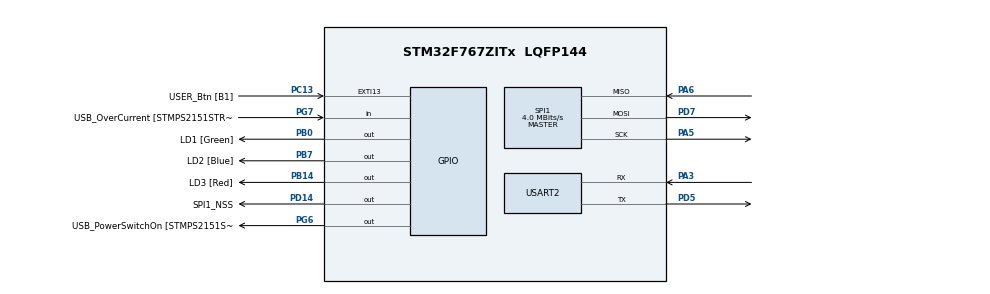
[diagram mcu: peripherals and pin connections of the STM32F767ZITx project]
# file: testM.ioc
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Dma.Request0=SPI1_RX
Dma.Request1=SPI1_TX
Dma.Request2=USART2_RX
Dma.Request3=USART2_TX
Dma.SPI1_RX.0.Direction=DMA_PERIPH_TO_MEMORY
Dma.SPI1_RX.0.FIFOMode=DMA_FIFOMODE_DISABLE
Dma.SPI1_RX.0.Instance=DMA2_Stream0
Dma.SPI1_RX.0.MemDataAlignment=DMA_MDATAALIGN_BYTE
Dma.SPI1_RX.0.MemInc=DMA_MINC_ENABLE
Dma.SPI1_RX.0.Mode=DMA_NORMAL
Dma.SPI1_RX.0.PeriphDataAlignment=DMA_PDATAALIGN_BYTE
Dma.SPI1_RX.0.PeriphInc=DMA_PINC_DISABLE
Dma.SPI1_RX.0.Priority=DMA_PRIORITY_LOW
Dma.SPI1_TX.1.Direction=DMA_MEMORY_TO_PERIPH
Dma.SPI1_TX.1.FIFOMode=DMA_FIFOMODE_DISABLE
Dma.SPI1_TX.1.Instance=DMA2_Stream3
Dma.SPI1_TX.1.MemDataAlignment=DMA_MDATAALIGN_BYTE
Dma.SPI1_TX.1.MemInc=DMA_MINC_ENABLE
Dma.SPI1_TX.1.Mode=DMA_NORMAL
Dma.SPI1_TX.1.PeriphDataAlignment=DMA_PDATAALIGN_BYTE
Dma.SPI1_TX.1.PeriphInc=DMA_PINC_DISABLE
Dma.SPI1_TX.1.Priority=DMA_PRIORITY_LOW
Dma.USART2_RX.2.Direction=DMA_PERIPH_TO_MEMORY
Dma.USART2_RX.2.FIFOMode=DMA_FIFOMODE_DISABLE
Dma.USART2_RX.2.Instance=DMA1_Stream5
Dma.USART2_RX.2.MemDataAlignment=DMA_MDATAALIGN_BYTE
Dma.USART2_RX.2.MemInc=DMA_MINC_ENABLE
Dma.USART2_RX.2.Mode=DMA_NORMAL
Dma.USART2_RX.2.PeriphDataAlignment=DMA_PDATAALIGN_BYTE
Dma.USART2_RX.2.PeriphInc=DMA_PINC_DISABLE
Dma.USART2_RX.2.Priority=DMA_PRIORITY_MEDIUM
Dma.USART2_TX.3.Direction=DMA_MEMORY_TO_PERIPH
Dma.USART2_TX.3.FIFOMode=DMA_FIFOMODE_DISABLE
Dma.USART2_TX.3.Instance=DMA1_Stream6
Dma.USART2_TX.3.MemDataAlignment=DMA_MDATAALIGN_BYTE
Dma.USART2_TX.3.MemInc=DMA_MINC_ENABLE
Dma.USART2_TX.3.Mode=DMA_NORMAL
Dma.USART2_TX.3.PeriphDataAlignment=DMA_PDATAALIGN_BYTE
Dma.USART2_TX.3.PeriphInc=DMA_PINC_DISABLE
Dma.USART2_TX.3.Priority=DMA_PRIORITY_MEDIUM
Mcu.Family=STM32F7
Mcu.Name=STM32F767ZITx
Mcu.Package=LQFP144
NVIC.DMA1_Stream5_IRQn=true\:0\:0\:false\:false\:true\:false\:true\:true
NVIC.DMA1_Stream6_IRQn=true\:0\:0\:false\:false\:true\:false\:true\:true
NVIC.DMA2_Stream0_IRQn=true\:0\:0\:false\:false\:true\:false\:true\:true
NVIC.DMA2_Stream3_IRQn=true\:0\:0\:false\:false\:true\:false\:true\:true
NVIC.PriorityGroup=NVIC_PRIORITYGROUP_4
NVIC.SPI1_IRQn=true\:0\:0\:false\:false\:true\:true\:true\:true
NVIC.USART2_IRQn=true\:0\:0\:false\:false\:true\:true\:true\:true
PA1.GPIO_Label=RMII_REF_CLK [LAN8742A-CZ-TR_REFCLK0]
PA1.Signal=ETH_REF_CLK
PA10.GPIO_Label=USB_ID
PA10.Signal=USB_OTG_FS_ID
PA11.GPIO_Label=USB_DM
PA11.Signal=USB_OTG_FS_DM
PA12.GPIO_Label=USB_DP
PA12.Signal=USB_OTG_FS_DP
PA13.GPIO_Label=TMS
PA13.Signal=SYS_JTMS-SWDIO
PA14.GPIO_Label=TCK
PA14.Signal=SYS_JTCK-SWCLK
PA2.GPIO_Label=RMII_MDIO [LAN8742A-CZ-TR_MDIO]
PA2.Signal=ETH_MDIO
PA3.Mode=Asynchronous
PA3.Signal=USART2_RX
PA5.Mode=Full_Duplex_Master
PA5.Signal=SPI1_SCK
PA6.Mode=Full_Duplex_Master
PA6.Signal=SPI1_MISO
PA7.GPIO_Label=RMII_CRS_DV [LAN8742A-CZ-TR_CRS_DV]
PA7.Signal=ETH_CRS_DV
PA8.GPIO_Label=USB_SOF [TP1]
PA8.Signal=USB_OTG_FS_SOF
PA9.GPIO_Label=USB_VBUS
PA9.Signal=USB_OTG_FS_VBUS
PB0.GPIO_Label=LD1 [Green]
PB0.Signal=GPIO_Output
PB13.GPIO_Label=RMII_TXD1 [LAN8742A-CZ-TR_TXD1]
PB13.Signal=ETH_TXD1
PB14.GPIO_Label=LD3 [Red]
PB14.Signal=GPIO_Output
PB3.GPIO_Label=SW0
PB3.Signal=SYS_JTDO-SWO
PB7.GPIO_Label=LD2 [Blue]
PB7.Signal=GPIO_Output
PC1.GPIO_Label=RMII_MDC [LAN8742A-CZ-TR_MDC]
PC1.Signal=ETH_MDC
PC13.GPIO_Label=USER_Btn [B1]
PC13.Signal=GPXTI13
PC14/OSC32_IN.Signal=RCC_OSC32_IN
PC15/OSC32_OUT.Signal=RCC_OSC32_OUT
PC4.GPIO_Label=RMII_RXD0 [LAN8742A-CZ-TR_RXD0]
PC4.Signal=ETH_RXD0
PC5.GPIO_Label=RMII_RXD1 [LAN8742A-CZ-TR_RXD1]
PC5.Signal=ETH_RXD1
PD14.GPIO_Label=SPI1_NSS
PD14.GPIO_PuPd=GPIO_NOPULL
PD14.Signal=GPIO_Output
PD5.Mode=Asynchronous
PD5.Signal=USART2_TX
PD7.Mode=Full_Duplex_Master
PD7.Signal=SPI1_MOSI
PD8.GPIO_Label=STLK_RX [STM32F103CBT6_PA3]
PD8.Signal=USART3_TX
PD9.GPIO_Label=STLK_TX [STM32F103CBT6_PA2]
PD9.Signal=USART3_RX
PG11.GPIO_Label=RMII_TX_EN [LAN8742A-CZ-TR_TXEN]
PG11.Signal=ETH_TX_EN
PG13.GPIO_Label=RMII_TXD0 [LAN8742A-CZ-TR_TXD0]
PG13.Signal=ETH_TXD0
PG6.GPIO_Label=USB_PowerSwitchOn [STMPS2151STR_EN]
PG6.Signal=GPIO_Output
PG7.GPIO_Label=USB_OverCurrent [STMPS2151STR_FAULT]
PG7.Signal=GPIO_Input
PH0/OSC_IN.GPIO_Label=MCO [STM32F103CBT6_PA8]
PH0/OSC_IN.Signal=RCC_OSC_IN
PH1/OSC_OUT.Signal=RCC_OSC_OUT
ProjectManager.HeapSize=0x200
ProjectManager.StackSize=0x400
ProjectManager.TargetToolchain=STM32CubeIDE
RCC.48MHZClocksFreq_Value=24000000
RCC.AHBFreq_Value=16000000
RCC.APB1CLKDivider=RCC_HCLK_DIV2
RCC.APB1Freq_Value=8000000
RCC.APB1TimFreq_Value=16000000
RCC.APB2Freq_Value=16000000
RCC.APB2TimFreq_Value=16000000
RCC.CortexFreq_Value=16000000
RCC.HCLKFreq_Value=16000000
RCC.HSE_VALUE=16000000
RCC.HSI_VALUE=16000000
RCC.LSE_VALUE=32768
RCC.PLLMUL=RCC_PLL_MUL9
RCC.PRESCALERUSB=RCC_USBCLKSOURCE_PLL_DIV1_5
RCC.SYSCLKFreq_VALUE=16000000
RCC.SYSCLKSourceVirtual=RCC_SYSCLKSOURCE_PLLCLK
RCC.USBFreq_Value=96000000
RCC.VCOOutputFreq_Value=192000000
SPI1.BaudRatePrescaler=SPI_BAUDRATEPRESCALER_4
SPI1.CalculateBaudRate=4.0 MBits/s
SPI1.DataSize=SPI_DATASIZE_8BIT
SPI1.Direction=SPI_DIRECTION_2LINES
SPI1.Mode=SPI_MODE_MASTER
SPI1.VirtualType=VM_MASTER
USART2.VirtualMode-Asynchronous=VM_ASYNC
VP_CRC_VS_CRC.Mode=CRC_Activate
board=NUCLEO-F767ZI

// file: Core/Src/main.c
/* USER CODE BEGIN Header */
/**
  ******************************************************************************
  * @file           : main.c
  * @brief          : Main program body
  ******************************************************************************
  * @attention
  *
  * Copyright (c) 2026 STMicroelectronics.
  * All rights reserved.
  *
  * This software is licensed under terms that can be found in the LICENSE file
  * in the root directory of this software component.
  * If no LICENSE file comes with this software, it is provided AS-IS.
  *
  ******************************************************************************
  */
/* USER CODE END Header */
#include "main.h"

/* USER CODE BEGIN Includes */
#include <stdio.h>
#include <string.h>
/* USER CODE END Includes */

/* USER CODE BEGIN PTD */
#define DATA_SIZE 512

// Structure de la trame de 520 octets
typedef struct __attribute__((packed)) {
    uint8_t  cmd;           // 0x01: Write, 0x02: Erase,
    uint32_t addr;          // Adresse Flash de destination
    uint16_t len;           // Toujours 512
    uint8_t  data[DATA_SIZE]; // Les données à flasher
    uint8_t  crc;           // XOR de vérification
} SpiFrame_t;
/* USER CODE END PTD */

CRC_HandleTypeDef hcrc;

SPI_HandleTypeDef hspi1;
DMA_HandleTypeDef hdma_spi1_rx;
DMA_HandleTypeDef hdma_spi1_tx;

UART_HandleTypeDef huart2;
DMA_HandleTypeDef hdma_usart2_rx;
DMA_HandleTypeDef hdma_usart2_tx;

/* USER CODE BEGIN PV */
uint8_t msg[] = "Communication via ST-LINK V3 CN3 : OK\r\n";
__attribute__((aligned(32))) SpiFrame_t frame_A;
__attribute__((aligned(32)))   SpiFrame_t frame_B;

SpiFrame_t *uart_rx_ptr = &frame_A;
SpiFrame_t *spi_tx_ptr  = &frame_B;

volatile uint8_t uart_rx_ready = 0;
__attribute__((aligned(32))) volatile uint8_t spi_tx_complete = 1;
volatile uint32_t dbg_bridge_count = 0;
/* USER CODE END PV */

void SystemClock_Config(void);
static void MX_GPIO_Init(void);
static void MX_DMA_Init(void);
static void MX_SPI1_Init(void);
static void MX_USART2_UART_Init(void);
static void MX_CRC_Init(void);
/* USER CODE BEGIN PFP */
void Send_SPI_Bridge_Frame(SpiFrame_t *frame_ptr);
void Enable_NonCacheable_Regions(void); // Add this line
/* USER CODE END PFP */

int main(void)
{

  /* MCU Configuration--------------------------------------------------------*/

  /* Reset of all peripherals, Initializes the Flash interface and the Systick. */
  HAL_Init();

  /* USER CODE BEGIN Init */
  Enable_NonCacheable_Regions();
  /* USER CODE END Init */

  /* Configure the system clock */
  SystemClock_Config();

  /* Initialize all configured peripherals */
  MX_GPIO_Init();
  MX_DMA_Init();
  MX_SPI1_Init();
  MX_USART2_UART_Init();
  MX_CRC_Init();
  /* USER CODE BEGIN 2 */
  HAL_GPIO_WritePin(GPIOD, SPI1_NSS_Pin, GPIO_PIN_SET);
  HAL_UART_Receive_DMA(&huart2, (uint8_t*)uart_rx_ptr, sizeof(SpiFrame_t));
  /* USER CODE END 2 */

  /* Infinite loop */
  /* USER CODE BEGIN WHILE */
  while (1)
  {
		if (uart_rx_ready)
	    	    {
	    	        uart_rx_ready = 0;
	    	        Send_SPI_Bridge_Frame(spi_tx_ptr);
	    	        dbg_bridge_count++;
	    	        HAL_GPIO_TogglePin(GPIOB, LD1_Pin);
	    	    }
    /* USER CODE END WHILE */

  }
}

void SystemClock_Config(void)
{
  RCC_OscInitTypeDef RCC_OscInitStruct = {0};
  RCC_ClkInitTypeDef RCC_ClkInitStruct = {0};

  __HAL_RCC_PWR_CLK_ENABLE();
  __HAL_PWR_VOLTAGESCALING_CONFIG(PWR_REGULATOR_VOLTAGE_SCALE1);

  // Configuration PLL pour 216MHz à partir du HSI (16MHz)
  RCC_OscInitStruct.OscillatorType = RCC_OSCILLATORTYPE_HSI;
  RCC_OscInitStruct.HSIState = RCC_HSI_ON;
  RCC_OscInitStruct.HSICalibrationValue = RCC_HSICALIBRATION_DEFAULT;
  RCC_OscInitStruct.PLL.PLLState = RCC_PLL_ON;
  RCC_OscInitStruct.PLL.PLLSource = RCC_PLLSOURCE_HSI;
  RCC_OscInitStruct.PLL.PLLM = 8;
  RCC_OscInitStruct.PLL.PLLN = 216;
  RCC_OscInitStruct.PLL.PLLP = RCC_PLLP_DIV2;
  RCC_OscInitStruct.PLL.PLLQ = 2;
  if (HAL_RCC_OscConfig(&RCC_OscInitStruct) != HAL_OK) { Error_Handler(); }

  // Activation de l'OverDrive pour atteindre 216MHz
  if (HAL_PWREx_EnableOverDrive() != HAL_OK) { Error_Handler(); }

  RCC_ClkInitStruct.ClockType = RCC_CLOCKTYPE_HCLK|RCC_CLOCKTYPE_SYSCLK
                              |RCC_CLOCKTYPE_PCLK1|RCC_CLOCKTYPE_PCLK2;
  RCC_ClkInitStruct.SYSCLKSource = RCC_SYSCLKSOURCE_PLLCLK;
  RCC_ClkInitStruct.AHBCLKDivider = RCC_SYSCLK_DIV1;
  RCC_ClkInitStruct.APB1CLKDivider = RCC_HCLK_DIV4;
  RCC_ClkInitStruct.APB2CLKDivider = RCC_HCLK_DIV2;

  if (HAL_RCC_ClockConfig(&RCC_ClkInitStruct, FLASH_LATENCY_7) != HAL_OK) { Error_Handler(); }
}

static void MX_CRC_Init(void)
{

  hcrc.Instance = CRC;
  hcrc.Init.DefaultPolynomialUse = DEFAULT_POLYNOMIAL_ENABLE;
  hcrc.Init.DefaultInitValueUse = DEFAULT_INIT_VALUE_ENABLE;
  hcrc.Init.InputDataInversionMode = CRC_INPUTDATA_INVERSION_NONE;
  hcrc.Init.OutputDataInversionMode = CRC_OUTPUTDATA_INVERSION_DISABLE;
  hcrc.InputDataFormat = CRC_INPUTDATA_FORMAT_BYTES;
  if (HAL_CRC_Init(&hcrc) != HAL_OK)
  {
    Error_Handler();
  }

}

static void MX_SPI1_Init(void)
{

  /* SPI1 parameter configuration*/
  hspi1.Instance = SPI1;
  hspi1.Init.Mode = SPI_MODE_MASTER;
  hspi1.Init.Direction = SPI_DIRECTION_2LINES;
  hspi1.Init.DataSize = SPI_DATASIZE_8BIT;
  hspi1.Init.CLKPolarity = SPI_POLARITY_LOW;
  hspi1.Init.CLKPhase = SPI_PHASE_1EDGE;
  hspi1.Init.NSS = SPI_NSS_SOFT;
  hspi1.Init.BaudRatePrescaler = SPI_BAUDRATEPRESCALER_16;
  hspi1.Init.FirstBit = SPI_FIRSTBIT_MSB;
  hspi1.Init.TIMode = SPI_TIMODE_DISABLE;
  hspi1.Init.CRCCalculation = SPI_CRCCALCULATION_DISABLE;
  hspi1.Init.CRCPolynomial = 7;
  hspi1.Init.CRCLength = SPI_CRC_LENGTH_DATASIZE;
  hspi1.Init.NSSPMode = SPI_NSS_PULSE_DISABLE;
  if (HAL_SPI_Init(&hspi1) != HAL_OK)
  {
    Error_Handler();
  }

}

static void MX_USART2_UART_Init(void)
{

  huart2.Instance = USART2;
  huart2.Init.BaudRate = 115200;
  huart2.Init.WordLength = UART_WORDLENGTH_8B;
  huart2.Init.StopBits = UART_STOPBITS_1;
  huart2.Init.Parity = UART_PARITY_NONE;
  huart2.Init.Mode = UART_MODE_TX_RX;
  huart2.Init.HwFlowCtl = UART_HWCONTROL_NONE;
  huart2.Init.OverSampling = UART_OVERSAMPLING_16;
  huart2.Init.OneBitSampling = UART_ONE_BIT_SAMPLE_DISABLE;
  huart2.AdvancedInit.AdvFeatureInit = UART_ADVFEATURE_NO_INIT;
  if (HAL_UART_Init(&huart2) != HAL_OK)
  {
    Error_Handler();
  }

}

static void MX_DMA_Init(void)
{

  /* DMA controller clock enable */
  __HAL_RCC_DMA2_CLK_ENABLE();
  __HAL_RCC_DMA1_CLK_ENABLE();

  /* DMA interrupt init */
  /* DMA1_Stream5_IRQn interrupt configuration */
  HAL_NVIC_SetPriority(DMA1_Stream5_IRQn, 0, 0);
  HAL_NVIC_EnableIRQ(DMA1_Stream5_IRQn);
  /* DMA1_Stream6_IRQn interrupt configuration */
  HAL_NVIC_SetPriority(DMA1_Stream6_IRQn, 0, 0);
  HAL_NVIC_EnableIRQ(DMA1_Stream6_IRQn);
  /* DMA2_Stream0_IRQn interrupt configuration */
  HAL_NVIC_SetPriority(DMA2_Stream0_IRQn, 0, 0);
  HAL_NVIC_EnableIRQ(DMA2_Stream0_IRQn);
  /* DMA2_Stream3_IRQn interrupt configuration */
  HAL_NVIC_SetPriority(DMA2_Stream3_IRQn, 0, 0);
  HAL_NVIC_EnableIRQ(DMA2_Stream3_IRQn);

}

static void MX_GPIO_Init(void)
{
  GPIO_InitTypeDef GPIO_InitStruct = {0};

  /* GPIO Ports Clock Enable */
  __HAL_RCC_GPIOC_CLK_ENABLE();
  __HAL_RCC_GPIOH_CLK_ENABLE();
  __HAL_RCC_GPIOA_CLK_ENABLE();
  __HAL_RCC_GPIOB_CLK_ENABLE();
  __HAL_RCC_GPIOD_CLK_ENABLE();
  __HAL_RCC_GPIOG_CLK_ENABLE();

  /*Configure GPIO pin Output Level */
  HAL_GPIO_WritePin(GPIOB, LD1_Pin|LD3_Pin|LD2_Pin, GPIO_PIN_RESET);

  /*Configure GPIO pin Output Level */
  HAL_GPIO_WritePin(SPI1_NSS_GPIO_Port, SPI1_NSS_Pin, GPIO_PIN_RESET);

  /*Configure GPIO pin Output Level */
  HAL_GPIO_WritePin(USB_PowerSwitchOn_GPIO_Port, USB_PowerSwitchOn_Pin, GPIO_PIN_RESET);

  /*Configure GPIO pin : USER_Btn_Pin */
  GPIO_InitStruct.Pin = USER_Btn_Pin;
  GPIO_InitStruct.Mode = GPIO_MODE_IT_RISING;
  GPIO_InitStruct.Pull = GPIO_NOPULL;
  HAL_GPIO_Init(USER_Btn_GPIO_Port, &GPIO_InitStruct);

  /*Configure GPIO pins : RMII_MDC_Pin RMII_RXD0_Pin RMII_RXD1_Pin */
  GPIO_InitStruct.Pin = RMII_MDC_Pin|RMII_RXD0_Pin|RMII_RXD1_Pin;
  GPIO_InitStruct.Mode = GPIO_MODE_AF_PP;
  GPIO_InitStruct.Pull = GPIO_NOPULL;
  GPIO_InitStruct.Speed = GPIO_SPEED_FREQ_VERY_HIGH;
  GPIO_InitStruct.Alternate = GPIO_AF11_ETH;
  HAL_GPIO_Init(GPIOC, &GPIO_InitStruct);

  /*Configure GPIO pins : RMII_REF_CLK_Pin RMII_MDIO_Pin RMII_CRS_DV_Pin */
  GPIO_InitStruct.Pin = RMII_REF_CLK_Pin|RMII_MDIO_Pin|RMII_CRS_DV_Pin;
  GPIO_InitStruct.Mode = GPIO_MODE_AF_PP;
  GPIO_InitStruct.Pull = GPIO_NOPULL;
  GPIO_InitStruct.Speed = GPIO_SPEED_FREQ_VERY_HIGH;
  GPIO_InitStruct.Alternate = GPIO_AF11_ETH;
  HAL_GPIO_Init(GPIOA, &GPIO_InitStruct);

  /*Configure GPIO pins : LD1_Pin LD3_Pin LD2_Pin */
  GPIO_InitStruct.Pin = LD1_Pin|LD3_Pin|LD2_Pin;
  GPIO_InitStruct.Mode = GPIO_MODE_OUTPUT_PP;
  GPIO_InitStruct.Pull = GPIO_NOPULL;
  GPIO_InitStruct.Speed = GPIO_SPEED_FREQ_LOW;
  HAL_GPIO_Init(GPIOB, &GPIO_InitStruct);

  /*Configure GPIO pin : RMII_TXD1_Pin */
  GPIO_InitStruct.Pin = RMII_TXD1_Pin;
  GPIO_InitStruct.Mode = GPIO_MODE_AF_PP;
  GPIO_InitStruct.Pull = GPIO_NOPULL;
  GPIO_InitStruct.Speed = GPIO_SPEED_FREQ_VERY_HIGH;
  GPIO_InitStruct.Alternate = GPIO_AF11_ETH;
  HAL_GPIO_Init(RMII_TXD1_GPIO_Port, &GPIO_InitStruct);

  /*Configure GPIO pins : STLK_RX_Pin STLK_TX_Pin */
  GPIO_InitStruct.Pin = STLK_RX_Pin|STLK_TX_Pin;
  GPIO_InitStruct.Mode = GPIO_MODE_AF_PP;
  GPIO_InitStruct.Pull = GPIO_NOPULL;
  GPIO_InitStruct.Speed = GPIO_SPEED_FREQ_VERY_HIGH;
  GPIO_InitStruct.Alternate = GPIO_AF7_USART2;
  HAL_GPIO_Init(GPIOD, &GPIO_InitStruct);

  /*Configure GPIO pin : SPI1_NSS_Pin */
  GPIO_InitStruct.Pin = SPI1_NSS_Pin;
  GPIO_InitStruct.Mode = GPIO_MODE_OUTPUT_PP;
  GPIO_InitStruct.Pull = GPIO_NOPULL;
  GPIO_InitStruct.Speed = GPIO_SPEED_FREQ_LOW;
  HAL_GPIO_Init(SPI1_NSS_GPIO_Port, &GPIO_InitStruct);

  /*Configure GPIO pin : USB_PowerSwitchOn_Pin */
  GPIO_InitStruct.Pin = USB_PowerSwitchOn_Pin;
  GPIO_InitStruct.Mode = GPIO_MODE_OUTPUT_PP;
  GPIO_InitStruct.Pull = GPIO_NOPULL;
  GPIO_InitStruct.Speed = GPIO_SPEED_FREQ_LOW;
  HAL_GPIO_Init(USB_PowerSwitchOn_GPIO_Port, &GPIO_InitStruct);

  /*Configure GPIO pin : USB_OverCurrent_Pin */
  GPIO_InitStruct.Pin = USB_OverCurrent_Pin;
  GPIO_InitStruct.Mode = GPIO_MODE_INPUT;
  GPIO_InitStruct.Pull = GPIO_NOPULL;
  HAL_GPIO_Init(USB_OverCurrent_GPIO_Port, &GPIO_InitStruct);

  /*Configure GPIO pins : USB_SOF_Pin USB_ID_Pin USB_DM_Pin USB_DP_Pin */
  GPIO_InitStruct.Pin = USB_SOF_Pin|USB_ID_Pin|USB_DM_Pin|USB_DP_Pin;
  GPIO_InitStruct.Mode = GPIO_MODE_AF_PP;
  GPIO_InitStruct.Pull = GPIO_NOPULL;
  GPIO_InitStruct.Speed = GPIO_SPEED_FREQ_VERY_HIGH;
  GPIO_InitStruct.Alternate = GPIO_AF10_OTG_FS;
  HAL_GPIO_Init(GPIOA, &GPIO_InitStruct);

  /*Configure GPIO pin : USB_VBUS_Pin */
  GPIO_InitStruct.Pin = USB_VBUS_Pin;
  GPIO_InitStruct.Mode = GPIO_MODE_INPUT;
  GPIO_InitStruct.Pull = GPIO_NOPULL;
  HAL_GPIO_Init(USB_VBUS_GPIO_Port, &GPIO_InitStruct);

  /*Configure GPIO pins : RMII_TX_EN_Pin RMII_TXD0_Pin */
  GPIO_InitStruct.Pin = RMII_TX_EN_Pin|RMII_TXD0_Pin;
  GPIO_InitStruct.Mode = GPIO_MODE_AF_PP;
  GPIO_InitStruct.Pull = GPIO_NOPULL;
  GPIO_InitStruct.Speed = GPIO_SPEED_FREQ_VERY_HIGH;
  GPIO_InitStruct.Alternate = GPIO_AF11_ETH;
  HAL_GPIO_Init(GPIOG, &GPIO_InitStruct);

}

/* USER CODE BEGIN 4 */

void Send_SPI_Bridge_Frame(SpiFrame_t *frame_ptr)
{
    // 1. Attendre que le transfert précédent soit terminé
    while (!spi_tx_complete);
    spi_tx_complete = 0;

    // 2. Calculer une taille alignée sur 32 octets (Cache Line)
    // 520 octets -> on nettoie 544 octets pour être sûr
    uint32_t aligned_size = (sizeof(SpiFrame_t) + 31) & ~31U;
    SCB_CleanDCache_by_Addr((uint32_t *)frame_ptr, aligned_size);

    // 3. Sélection du Slave (NSS Bas)
    HAL_GPIO_WritePin(GPIOD, SPI1_NSS_Pin, GPIO_PIN_RESET);

    // 4. Délai de "Lead Time"
    // À 216MHz, HAL_Delay(2) est énorme. Si tu es toujours à 16MHz, garde-le.
    // Si tu es passé à 216MHz, utilise une boucle simple :
    for(volatile int i = 0; i < 2000; i++);

    // 5. Lancement du DMA
    if (HAL_SPI_Transmit_DMA(&hspi1, (uint8_t*)frame_ptr, sizeof(SpiFrame_t)) != HAL_OK) {
        // Gestion d'erreur si le DMA est occupé
        spi_tx_complete = 1;
        HAL_GPIO_WritePin(GPIOD, SPI1_NSS_Pin, GPIO_PIN_SET);
        return;
    }

    // 6. Commande VERIFY (0x04)
    if (frame_ptr->cmd == 0x04) {
        // On attend que le DMA SPI soit fini AVANT de demander le checksum
        while (!spi_tx_complete);

        uint8_t checksum_received = 0;
        HAL_Delay(50); // Temps pour que la G4 calcule son XOR sur la Flash

        // On repasse en NSS Bas pour la lecture (si remonté par le callback)
        HAL_GPIO_WritePin(GPIOD, SPI1_NSS_Pin, GPIO_PIN_RESET);
        HAL_SPI_Receive(&hspi1, &checksum_received, 1, 200);
        HAL_GPIO_WritePin(GPIOD, SPI1_NSS_Pin, GPIO_PIN_SET);

        HAL_UART_Transmit(&huart2, &checksum_received, 1, 100);
    }
}

void HAL_SPI_TxCpltCallback(SPI_HandleTypeDef *hspi)
{
    if (hspi->Instance == SPI1) {
        // Attendre un peu que les derniers bits passent
    	while (__HAL_SPI_GET_FLAG(hspi, SPI_FLAG_BSY));
        // Puis NSS up
        HAL_GPIO_WritePin(GPIOD, SPI1_NSS_Pin, GPIO_PIN_SET);
        spi_tx_complete = 1;
    }
}
void HAL_UART_RxCpltCallback(UART_HandleTypeDef *huart)
{
    if (huart->Instance == USART2)
    {
        // Échange atomique des buffers
        SpiFrame_t *temp = uart_rx_ptr;
        uart_rx_ptr = spi_tx_ptr;
        spi_tx_ptr = temp;

        // Relancer la réception sur le nouveau buffer vide
        HAL_UART_Receive_DMA(&huart2, (uint8_t*)uart_rx_ptr, sizeof(SpiFrame_t));

        // Signaler au main
        uart_rx_ready = 1;
    }
}

void Enable_NonCacheable_Regions(void)
{
    HAL_MPU_Disable();

    MPU_Region_InitTypeDef MPU_InitStruct = {0};

    // Région 0: Buffer SPI (non-cacheable)
    MPU_InitStruct.Enable = MPU_REGION_ENABLE;
    MPU_InitStruct.Number = MPU_REGION_NUMBER0;
    MPU_InitStruct.BaseAddress = (uint32_t)&frame_A;
    MPU_InitStruct.Size = MPU_REGION_SIZE_2KB;
    MPU_InitStruct.SubRegionDisable = 0x0;
    MPU_InitStruct.TypeExtField = MPU_TEX_LEVEL1;
    MPU_InitStruct.AccessPermission = MPU_REGION_FULL_ACCESS;
    MPU_InitStruct.DisableExec = MPU_INSTRUCTION_ACCESS_ENABLE;
    MPU_InitStruct.IsShareable = MPU_ACCESS_SHAREABLE;
    MPU_InitStruct.IsCacheable = MPU_ACCESS_NOT_CACHEABLE;  // �? CRUCIAL
    MPU_InitStruct.IsBufferable = MPU_ACCESS_BUFFERABLE;

    HAL_MPU_ConfigRegion(&MPU_InitStruct);
    HAL_MPU_Enable(MPU_PRIVILEGED_DEFAULT);
}
/* USER CODE END 4 */

void Error_Handler(void)
{
  __disable_irq();
  while (1)
  {
  }
}
